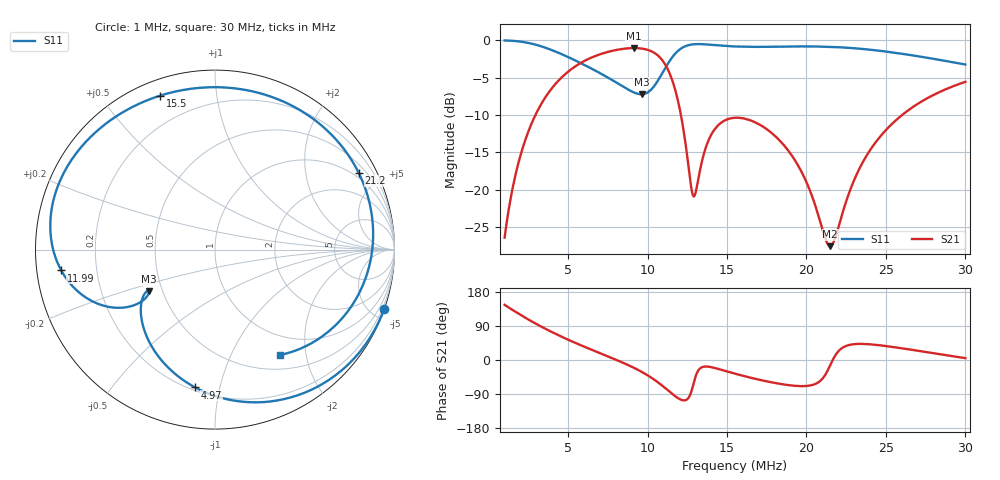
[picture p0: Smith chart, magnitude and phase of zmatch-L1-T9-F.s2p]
# HZ S RI R 50
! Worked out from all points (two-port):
!   505 points, 1 MHz to 30 MHz, reference 50 ohm
!   highest |S21| = -1.02 dB at 9.113 MHz (marker M1); lowest = -27.6 dB at 21.48 MHz (marker M2)
!   |S21| within 3 dB of the highest: 5.092 MHz to 11.3 MHz (6.212 MHz wide, 75.8 % of centre)
!   lowest |S11| = -7.2 dB at 9.631 MHz (marker M3), VSWR 2.54, Z = 21 - j12 ohm
!   |S11| at or under -10 dB: nowhere
!   S12 and S22 are empty: the file has one direction only
!   S11 on the Smith chart (normalised r, x): 1 MHz: 0.01, -5.88; 4.97 MHz: 0.22, -0.84; 11.99 MHz: 0.07, -0.07; 15.5 MHz: 0.07, +0.70; 21.2 MHz: 0.79, +3.84; 30 MHz: 0.70, -1.56
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1000000  0.943 -0.3305  -0.0394 0.027  0 0  0 0
1748020  0.8158 -0.5584  -0.0781 0.1094  0 0  0 0
2553580  0.6023 -0.7463  -0.0679 0.2457  0 0  0 0
3646840  0.2539 -0.8502  0.0694 0.4229  0 0  0 0
4970260  -0.1106 -0.7679  0.3602 0.4976  0 0  0 0
5833360  -0.2712 -0.6467  0.5575 0.4403  0 0  0 0
7617100  -0.4113 -0.3721  0.8369 0.1095  0 0  0 0
9113140  -0.383 -0.2353  0.835 -0.3042  0 0  0 0
9631000  -0.3689 -0.2319  0.7527 -0.4592  0 0  0 0
1.066672e7  -0.4461 -0.3082  0.4013 -0.6792  0 0  0 0
1.124212e7  -0.6131 -0.3146  0.1271 -0.6368  0 0  0 0
1.199014e7  -0.8566 -0.1159  -0.0781 -0.3521  0 0  0 0
1.291078e7  -0.8951 0.2944  0.0463 -0.0773  0 0  0 0
1.400404e7  -0.6807 0.6398  0.2209 -0.0758  0 0  0 0
1.550008e7  -0.3038 0.8585  0.2453 -0.1787  0 0  0 0
1.8262e7  0.3487 0.8383  0.1001 -0.1919  0 0  0 0
2.033344e7  0.7063 0.5757  0.0368 -0.0839  0 0  0 0
2.119654e7  0.8006 0.4272  0.0369 -0.0289  0 0  0 0
2.148424e7  0.8242 0.3751  0.0406 -0.0105  0 0  0 0
2.332552e7  0.8797 0.0385  0.1018 0.0934  0 0  0 0
2.51668e7  0.7999 -0.2491  0.2125 0.1536  0 0  0 0
3.000016e7  0.3614 -0.5875  0.5263 0.0444  0 0  0 0
